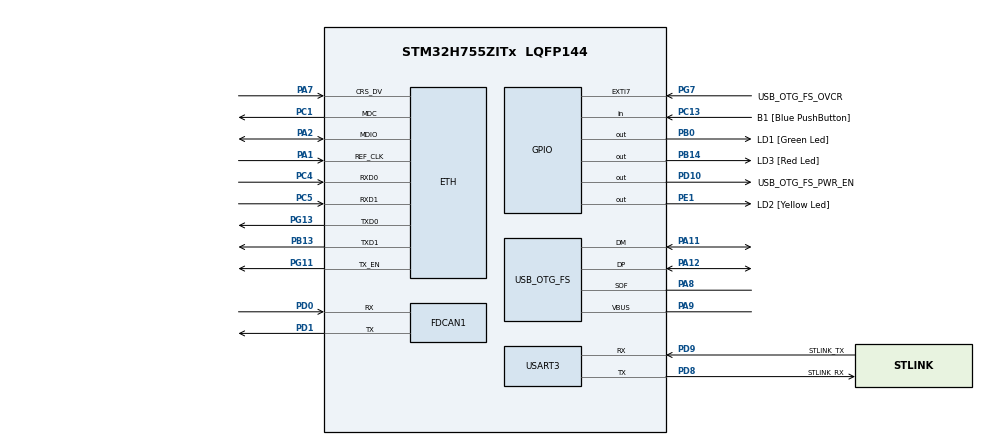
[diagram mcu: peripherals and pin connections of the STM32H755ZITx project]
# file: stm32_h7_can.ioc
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CortexM4.IPs=FATFS_M4\:I,FREERTOS_M4\:I,IWDG2\:I,RCC,WWDG2\:I,DMA,BDMA,MDMA,NVIC2\:I,ETH,USART3,DEBUG,USB_DEVICE_M4\:I,USB_HOST_M4\:I,PDM2PCM_M4\:I,PWR,RESMGR_UTILITY,SYS_M4\:I,CORTEX_M4\:I,OPENAMP_M4\:I,VREFBUF,GPIO
CortexM7.IPs=FATFS_M7\:I,FREERTOS_M7\:I,IWDG1\:I,RCC\:I,WWDG1\:I,DMA\:I,BDMA\:I,MDMA\:I,NVIC1\:I,ETH\:I,USART3\:I,USB_OTG_FS\:I,SYS\:I,CORTEX_M7\:I,DEBUG\:I,USB_DEVICE_M7\:I,USB_HOST_M7\:I,PDM2PCM_M7\:I,PWR\:I,RESMGR_UTILITY\:I,OPENAMP_M7\:I,VREFBUF\:I,GPIO\:I,FDCAN1\:I
ETH.MediaInterface=HAL_ETH_RMII_MODE
FDCAN1.CalculateBaudRateNominal=1499999
FDCAN1.CalculateTimeBitNominal=666
FDCAN1.CalculateTimeQuantumNominal=8.333333333333334
FDCAN1.NominalPrescaler=2
FDCAN1.NominalSyncJumpWidth=8
FDCAN1.NominalTimeSeg1=0x3F
FDCAN1.NominalTimeSeg2=16
FDCAN1.ProtocolException=ENABLE
FDCAN1.RxFifo0ElmtsNbr=1
FDCAN1.StdFiltersNbr=1
FDCAN1.TxFifoQueueElmtsNbr=1
Mcu.Family=STM32H7
Mcu.Name=STM32H755ZITx
Mcu.Package=LQFP144
NVIC1.PriorityGroup=NVIC_PRIORITYGROUP_4
NVIC2.PriorityGroup=NVIC_PRIORITYGROUP_4
PA1.Mode=RMII
PA1.PinAttribute=CortexM7
PA1.Signal=ETH_REF_CLK
PA11.Mode=Device_Only
PA11.PinAttribute=CortexM7
PA11.Signal=USB_OTG_FS_DM
PA12.Mode=Device_Only
PA12.PinAttribute=CortexM7
PA12.Signal=USB_OTG_FS_DP
PA2.Mode=RMII
PA2.PinAttribute=CortexM7
PA2.Signal=ETH_MDIO
PA7.Mode=RMII
PA7.PinAttribute=CortexM7
PA7.Signal=ETH_CRS_DV
PA8.Mode=Activate_SOF_FS
PA8.PinAttribute=CortexM7
PA8.Signal=USB_OTG_FS_SOF
PA9.Mode=Activate_VBUS
PA9.PinAttribute=CortexM7
PA9.Signal=USB_OTG_FS_VBUS
PB0.GPIO_Label=LD1 [Green Led]
PB0.PinAttribute=Free
PB0.Signal=GPIO_Output
PB13.Mode=RMII
PB13.PinAttribute=CortexM7
PB13.Signal=ETH_TXD1
PB14.GPIO_Label=LD3 [Red Led]
PB14.PinAttribute=Free
PB14.Signal=GPIO_Output
PC1.Mode=RMII
PC1.PinAttribute=CortexM7
PC1.Signal=ETH_MDC
PC13.GPIO_Label=B1 [Blue PushButton]
PC13.PinAttribute=Free
PC13.Signal=GPIO_Input
PC14-OSC32_IN\ (OSC32_IN).Mode=LSE-External-Oscillator
PC14-OSC32_IN\ (OSC32_IN).PinAttribute=CortexM7
PC14-OSC32_IN\ (OSC32_IN).Signal=RCC_OSC32_IN
PC15-OSC32_OUT\ (OSC32_OUT).Mode=LSE-External-Oscillator
PC15-OSC32_OUT\ (OSC32_OUT).PinAttribute=CortexM7
PC15-OSC32_OUT\ (OSC32_OUT).Signal=RCC_OSC32_OUT
PC4.Mode=RMII
PC4.PinAttribute=CortexM7
PC4.Signal=ETH_RXD0
PC5.Mode=RMII
PC5.PinAttribute=CortexM7
PC5.Signal=ETH_RXD1
PD0.Mode=FDCAN_Activate
PD0.PinAttribute=CortexM7
PD0.Signal=FDCAN1_RX
PD1.Mode=FDCAN_Activate
PD1.PinAttribute=CortexM7
PD1.Signal=FDCAN1_TX
PD10.GPIO_Label=USB_OTG_FS_PWR_EN
PD10.PinAttribute=Free
PD10.Signal=GPIO_Output
PD8.GPIO_Label=STLINK_RX
PD8.Mode=Asynchronous
PD8.PinAttribute=CortexM7
PD8.Signal=USART3_TX
PD9.GPIO_Label=STLINK_TX
PD9.Mode=Asynchronous
PD9.PinAttribute=CortexM7
PD9.Signal=USART3_RX
PE1.GPIO_Label=LD2 [Yellow Led]
PE1.PinAttribute=Free
PE1.Signal=GPIO_Output
PG11.Mode=RMII
PG11.PinAttribute=CortexM7
PG11.Signal=ETH_TX_EN
PG13.Mode=RMII
PG13.PinAttribute=CortexM7
PG13.Signal=ETH_TXD0
PG7.GPIO_Label=USB_OTG_FS_OVCR
PG7.PinAttribute=Free
PG7.Signal=GPXTI7
PH0-OSC_IN\ (PH0).Mode=HSE-External-Clock-Source
PH0-OSC_IN\ (PH0).PinAttribute=CortexM7
PH0-OSC_IN\ (PH0).Signal=RCC_OSC_IN
PH1-OSC_OUT\ (PH1).PinAttribute=CortexM7
PH1-OSC_OUT\ (PH1).Signal=RCC_OSC_OUT
ProjectManager.HeapSize=M4-0x200,M7-0x200
ProjectManager.StackSize=M4-0x400,M7-0x400
ProjectManager.TargetToolchain=STM32CubeIDE
RCC.ADCFreq_Value=129000000
RCC.APB1Freq_Value=30000000
RCC.APB2Freq_Value=60000000
RCC.APB3Freq_Value=60000000
RCC.APB4Freq_Value=60000000
RCC.CortexFreq_Value=120000000
RCC.D1CPRE=RCC_SYSCLK_DIV2
RCC.D2PPRE1=RCC_APB1_DIV2
RCC.DIVM1=4
RCC.DIVN1=60
RCC.DIVP1=4
RCC.DIVQ1=4
RCC.HCLKFreq_Value=60000000
RCC.HPRE=RCC_HCLK_DIV2
RCC.HSE_VALUE=8000000
RCC.PLL2FRACN=0
RCC.PLL3FRACN=0
RCC.PLLFRACN=0
RCC.PLLSourceVirtualString=RCC_PLLSOURCE_HSI
RCC.PWR_Regulator_Voltage_Scale=PWR_REGULATOR_VOLTAGE_SCALE2
RCC.SYSCLKFreq_VALUE=240000000
RCC.SYSCLKSource=RCC_SYSCLKSOURCE_PLLCLK
RCC.SupplySource=PWR_DIRECT_SMPS_SUPPLY
RCC.USBFreq_Value=240000000
USART3.VirtualMode-Asynchronous=VM_ASYNC
USB_OTG_FS.VirtualMode=Device_Only
VP_SYS_M4_VS_Systick.Mode=SysTick
board=NUCLEO-H755ZI-Q

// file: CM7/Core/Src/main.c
/* USER CODE BEGIN Header */
/**
  ******************************************************************************
  * @file           : main.c
  * @brief          : Main program body
  ******************************************************************************
  * @attention
  *
  * Copyright (c) 2024 STMicroelectronics.
  * All rights reserved.
  *
  * This software is licensed under terms that can be found in the LICENSE file
  * in the root directory of this software component.
  * If no LICENSE file comes with this software, it is provided AS-IS.
  *
  ******************************************************************************
  */
/* USER CODE END Header */
#include "main.h"
#include "string.h"

/* USER CODE BEGIN PD */

#ifndef HSEM_ID_0
#define HSEM_ID_0 (0U) /* HW semaphore 0*/
#endif
/* USER CODE END PD */

#if defined ( __ICCARM__ ) /*!< IAR Compiler */
#pragma location=0x30000000
ETH_DMADescTypeDef  DMARxDscrTab[ETH_RX_DESC_CNT]; /* Ethernet Rx DMA Descriptors */
#pragma location=0x30000200
ETH_DMADescTypeDef  DMATxDscrTab[ETH_TX_DESC_CNT]; /* Ethernet Tx DMA Descriptors */

#elif defined ( __CC_ARM )  /* MDK ARM Compiler */

__attribute__((at(0x30000000))) ETH_DMADescTypeDef  DMARxDscrTab[ETH_RX_DESC_CNT]; /* Ethernet Rx DMA Descriptors */
__attribute__((at(0x30000200))) ETH_DMADescTypeDef  DMATxDscrTab[ETH_TX_DESC_CNT]; /* Ethernet Tx DMA Descriptors */

#elif defined ( __GNUC__ ) /* GNU Compiler */
ETH_DMADescTypeDef DMARxDscrTab[ETH_RX_DESC_CNT] __attribute__((section(".RxDecripSection"))); /* Ethernet Rx DMA Descriptors */
ETH_DMADescTypeDef DMATxDscrTab[ETH_TX_DESC_CNT] __attribute__((section(".TxDecripSection")));   /* Ethernet Tx DMA Descriptors */

#endif

ETH_TxPacketConfig TxConfig;

ETH_HandleTypeDef heth;

FDCAN_HandleTypeDef hfdcan1;

UART_HandleTypeDef huart3;

PCD_HandleTypeDef hpcd_USB_OTG_FS;

/* USER CODE BEGIN PV */
FDCAN_FilterTypeDef sFilterConfig;
FDCAN_TxHeaderTypeDef TxHeader;
FDCAN_RxHeaderTypeDef RxHeader;
uint8_t TxData[8] = {0x10, 0x34, 0x54, 0x76, 0x98, 0x00, 0x11, 0x22};
uint8_t RxData[8];
/* USER CODE END PV */

void SystemClock_Config(void);
static void MX_GPIO_Init(void);
static void MX_ETH_Init(void);
static void MX_USART3_UART_Init(void);
static void MX_USB_OTG_FS_PCD_Init(void);
static void MX_FDCAN1_Init(void);

int main(void)
{
/* USER CODE BEGIN Boot_Mode_Sequence_0 */
  int32_t timeout;
/* USER CODE END Boot_Mode_Sequence_0 */

/* USER CODE BEGIN Boot_Mode_Sequence_1 */
  /* Wait until CPU2 boots and enters in stop mode or timeout*/
  timeout = 0xFFFF;
  while((__HAL_RCC_GET_FLAG(RCC_FLAG_D2CKRDY) != RESET) && (timeout-- > 0));
  if ( timeout < 0 )
  {
  Error_Handler();
  }
/* USER CODE END Boot_Mode_Sequence_1 */
  /* MCU Configuration--------------------------------------------------------*/

  /* Reset of all peripherals, Initializes the Flash interface and the Systick. */
  HAL_Init();

  /* Configure the system clock */
  SystemClock_Config();
/* USER CODE BEGIN Boot_Mode_Sequence_2 */
/* When system initialization is finished, Cortex-M7 will release Cortex-M4 by means of
HSEM notification */
/*HW semaphore Clock enable*/
__HAL_RCC_HSEM_CLK_ENABLE();
/*Take HSEM */
HAL_HSEM_FastTake(HSEM_ID_0);
/*Release HSEM in order to notify the CPU2(CM4)*/
HAL_HSEM_Release(HSEM_ID_0,0);
/* wait until CPU2 wakes up from stop mode */
timeout = 0xFFFF;
while((__HAL_RCC_GET_FLAG(RCC_FLAG_D2CKRDY) == RESET) && (timeout-- > 0));
if ( timeout < 0 )
{
Error_Handler();
}
/* USER CODE END Boot_Mode_Sequence_2 */

  /* Initialize all configured peripherals */
  MX_GPIO_Init();
  MX_ETH_Init();
  MX_USART3_UART_Init();
  MX_USB_OTG_FS_PCD_Init();
  MX_FDCAN1_Init();

  /* Infinite loop */
  /* USER CODE BEGIN WHILE */
  printf("Welcome to the CANbus!!!\n\r");
//  while (1){
//  	while (HAL_FDCAN_GetRxMessage(&hfdcan1, FDCAN_RX_FIFO0, &RxHeader, RxData) != HAL_OK);
//  	HAL_Delay(10);
//  	printf("\n\rCAN ID: %lx", RxHeader.Identifier);
//  	//HAL_GPIO_TogglePin(LD1_GPIO_Port,LD1_Pin);
//  	HAL_Delay(100); /*AAO-*/
//  }

  while (1) {
      // Wait until a CAN message is received
      while (HAL_FDCAN_GetRxMessage(&hfdcan1, FDCAN_RX_FIFO0, &RxHeader, RxData) != HAL_OK);

      // Delay for 10 ms
      HAL_Delay(10);

      // Print CAN ID
      printf("\n\r0x%lx", RxHeader.Identifier);

      // Print the CAN data length and data bytes
      printf(" [%lu]", RxHeader.DataLength >> 16);  // Data length is stored in bits 16-19
      printf(" ");

      // Loop through each byte of the CAN message data and print it
      for (int i = 0; i < (RxHeader.DataLength >> 16); i++) {
          printf("0x%02X ", RxData[i]);  // Print each byte in hexadecimal
      }

      // Optional: toggle LED for visual feedback (commented out)
      // HAL_GPIO_TogglePin(LD1_GPIO_Port, LD1_Pin);

      // Delay for 100 ms
      HAL_Delay(100);
  }

    /* USER CODE END WHILE */

}

void SystemClock_Config(void)
{
  RCC_OscInitTypeDef RCC_OscInitStruct = {0};
  RCC_ClkInitTypeDef RCC_ClkInitStruct = {0};

  /** Supply configuration update enable
  */
  HAL_PWREx_ConfigSupply(PWR_DIRECT_SMPS_SUPPLY);

  /** Configure the main internal regulator output voltage
  */
  __HAL_PWR_VOLTAGESCALING_CONFIG(PWR_REGULATOR_VOLTAGE_SCALE2);

  while(!__HAL_PWR_GET_FLAG(PWR_FLAG_VOSRDY)) {}

  /** Initializes the RCC Oscillators according to the specified parameters
  * in the RCC_OscInitTypeDef structure.
  */
  RCC_OscInitStruct.OscillatorType = RCC_OSCILLATORTYPE_HSE;
  RCC_OscInitStruct.HSEState = RCC_HSE_BYPASS;
  RCC_OscInitStruct.PLL.PLLState = RCC_PLL_ON;
  RCC_OscInitStruct.PLL.PLLSource = RCC_PLLSOURCE_HSE;
  RCC_OscInitStruct.PLL.PLLM = 1;
  RCC_OscInitStruct.PLL.PLLN = 20;
  RCC_OscInitStruct.PLL.PLLP = 2;
  RCC_OscInitStruct.PLL.PLLQ = 4;
  RCC_OscInitStruct.PLL.PLLR = 2;
  RCC_OscInitStruct.PLL.PLLRGE = RCC_PLL1VCIRANGE_3;
  RCC_OscInitStruct.PLL.PLLVCOSEL = RCC_PLL1VCOMEDIUM;
  RCC_OscInitStruct.PLL.PLLFRACN = 0;
  if (HAL_RCC_OscConfig(&RCC_OscInitStruct) != HAL_OK)
  {
    Error_Handler();
  }

  /** Initializes the CPU, AHB and APB buses clocks
  */
  RCC_ClkInitStruct.ClockType = RCC_CLOCKTYPE_HCLK|RCC_CLOCKTYPE_SYSCLK
                              |RCC_CLOCKTYPE_PCLK1|RCC_CLOCKTYPE_PCLK2
                              |RCC_CLOCKTYPE_D3PCLK1|RCC_CLOCKTYPE_D1PCLK1;
  RCC_ClkInitStruct.SYSCLKSource = RCC_SYSCLKSOURCE_PLLCLK;
  RCC_ClkInitStruct.SYSCLKDivider = RCC_SYSCLK_DIV1;
  RCC_ClkInitStruct.AHBCLKDivider = RCC_HCLK_DIV1;
  RCC_ClkInitStruct.APB3CLKDivider = RCC_APB3_DIV1;
  RCC_ClkInitStruct.APB1CLKDivider = RCC_APB1_DIV2;
  RCC_ClkInitStruct.APB2CLKDivider = RCC_APB2_DIV1;
  RCC_ClkInitStruct.APB4CLKDivider = RCC_APB4_DIV1;

  if (HAL_RCC_ClockConfig(&RCC_ClkInitStruct, FLASH_LATENCY_1) != HAL_OK)
  {
    Error_Handler();
  }
}

static void MX_ETH_Init(void)
{

   static uint8_t MACAddr[6];

  heth.Instance = ETH;
  MACAddr[0] = 0x00;
  MACAddr[1] = 0x80;
  MACAddr[2] = 0xE1;
  MACAddr[3] = 0x00;
  MACAddr[4] = 0x00;
  MACAddr[5] = 0x00;
  heth.Init.MACAddr = &MACAddr[0];
  heth.Init.MediaInterface = HAL_ETH_RMII_MODE;
  heth.Init.TxDesc = DMATxDscrTab;
  heth.Init.RxDesc = DMARxDscrTab;
  heth.Init.RxBuffLen = 1524;

  if (HAL_ETH_Init(&heth) != HAL_OK)
  {
    Error_Handler();
  }

  memset(&TxConfig, 0 , sizeof(ETH_TxPacketConfig));
  TxConfig.Attributes = ETH_TX_PACKETS_FEATURES_CSUM | ETH_TX_PACKETS_FEATURES_CRCPAD;
  TxConfig.ChecksumCtrl = ETH_CHECKSUM_IPHDR_PAYLOAD_INSERT_PHDR_CALC;
  TxConfig.CRCPadCtrl = ETH_CRC_PAD_INSERT;

}

static void MX_FDCAN1_Init(void)
{

  hfdcan1.Instance = FDCAN1;
  hfdcan1.Init.FrameFormat = FDCAN_FRAME_CLASSIC;
  hfdcan1.Init.Mode = FDCAN_MODE_NORMAL;
  hfdcan1.Init.AutoRetransmission = DISABLE;
  hfdcan1.Init.TransmitPause = DISABLE;
  hfdcan1.Init.ProtocolException = ENABLE;
  hfdcan1.Init.NominalPrescaler = 2;
  hfdcan1.Init.NominalSyncJumpWidth = 8;
  hfdcan1.Init.NominalTimeSeg1 = 0x3F;
  hfdcan1.Init.NominalTimeSeg2 = 16;
  hfdcan1.Init.DataPrescaler = 1;
  hfdcan1.Init.DataSyncJumpWidth = 1;
  hfdcan1.Init.DataTimeSeg1 = 1;
  hfdcan1.Init.DataTimeSeg2 = 1;
  hfdcan1.Init.MessageRAMOffset = 0;
  hfdcan1.Init.StdFiltersNbr = 1;
  hfdcan1.Init.ExtFiltersNbr = 0;
  hfdcan1.Init.RxFifo0ElmtsNbr = 1;
  hfdcan1.Init.RxFifo0ElmtSize = FDCAN_DATA_BYTES_8;
  hfdcan1.Init.RxFifo1ElmtsNbr = 0;
  hfdcan1.Init.RxFifo1ElmtSize = FDCAN_DATA_BYTES_8;
  hfdcan1.Init.RxBuffersNbr = 0;
  hfdcan1.Init.RxBufferSize = FDCAN_DATA_BYTES_8;
  hfdcan1.Init.TxEventsNbr = 0;
  hfdcan1.Init.TxBuffersNbr = 0;
  hfdcan1.Init.TxFifoQueueElmtsNbr = 1;
  hfdcan1.Init.TxFifoQueueMode = FDCAN_TX_FIFO_OPERATION;
  hfdcan1.Init.TxElmtSize = FDCAN_DATA_BYTES_8;
  if (HAL_FDCAN_Init(&hfdcan1) != HAL_OK)
  {
    Error_Handler();
  }
  /* USER CODE BEGIN FDCAN1_Init 2 */
  /*AAO+*/
   /* Configure Rx filter */
    sFilterConfig.IdType = FDCAN_STANDARD_ID;
    sFilterConfig.FilterIndex = 0;
    sFilterConfig.FilterType = FDCAN_FILTER_MASK;
    sFilterConfig.FilterConfig = FDCAN_FILTER_TO_RXFIFO0;
    // Default
//    sFilterConfig.FilterID1 = 0x000; // Filter
//    sFilterConfig.FilterID2 = 0x000; // Mask
    // InClass CAN
    sFilterConfig.FilterID1 = 0x300; // Filter
    sFilterConfig.FilterID2 = 0x700; // Mask

//    sFilterConfig.FilterID1 = 0x617; // Filter
//    sFilterConfig.FilterID2 = 0x7FF; // Mask

    /* Configure global filter to reject all non-matching frames */
    HAL_FDCAN_ConfigGlobalFilter(&hfdcan1, FDCAN_REJECT, FDCAN_REJECT, FDCAN_REJECT_REMOTE, FDCAN_REJECT_REMOTE);

    if (HAL_FDCAN_ConfigFilter(&hfdcan1, &sFilterConfig) != HAL_OK)
      {
         /* Filter configuration Error */
         Error_Handler();
      }
     /* Start the FDCAN module */
    if (HAL_FDCAN_Start(&hfdcan1) != HAL_OK) {
      }
         /* Start Error */
    if (HAL_FDCAN_ActivateNotification(&hfdcan1, FDCAN_IT_RX_FIFO0_NEW_MESSAGE, 0) != HAL_OK) {
      }
         /* Notification Error */

     /* Configure Tx buffer message */
    TxHeader.Identifier = 0x111;
    TxHeader.IdType = FDCAN_STANDARD_ID;
    TxHeader.TxFrameType = FDCAN_DATA_FRAME;
    TxHeader.DataLength = FDCAN_DLC_BYTES_12;
    TxHeader.ErrorStateIndicator = FDCAN_ESI_ACTIVE;
    TxHeader.BitRateSwitch = FDCAN_BRS_ON;
    TxHeader.FDFormat = FDCAN_FD_CAN;
    TxHeader.TxEventFifoControl = FDCAN_NO_TX_EVENTS;
    TxHeader.MessageMarker = 0x00;
   /*AAO-*/
  /* USER CODE END FDCAN1_Init 2 */

}

static void MX_USART3_UART_Init(void)
{

  huart3.Instance = USART3;
  huart3.Init.BaudRate = 115200;
  huart3.Init.WordLength = UART_WORDLENGTH_8B;
  huart3.Init.StopBits = UART_STOPBITS_1;
  huart3.Init.Parity = UART_PARITY_NONE;
  huart3.Init.Mode = UART_MODE_TX_RX;
  huart3.Init.HwFlowCtl = UART_HWCONTROL_NONE;
  huart3.Init.OverSampling = UART_OVERSAMPLING_16;
  huart3.Init.OneBitSampling = UART_ONE_BIT_SAMPLE_DISABLE;
  huart3.Init.ClockPrescaler = UART_PRESCALER_DIV1;
  huart3.AdvancedInit.AdvFeatureInit = UART_ADVFEATURE_NO_INIT;
  if (HAL_UART_Init(&huart3) != HAL_OK)
  {
    Error_Handler();
  }
  if (HAL_UARTEx_SetTxFifoThreshold(&huart3, UART_TXFIFO_THRESHOLD_1_8) != HAL_OK)
  {
    Error_Handler();
  }
  if (HAL_UARTEx_SetRxFifoThreshold(&huart3, UART_RXFIFO_THRESHOLD_1_8) != HAL_OK)
  {
    Error_Handler();
  }
  if (HAL_UARTEx_DisableFifoMode(&huart3) != HAL_OK)
  {
    Error_Handler();
  }

}

static void MX_USB_OTG_FS_PCD_Init(void)
{

  hpcd_USB_OTG_FS.Instance = USB_OTG_FS;
  hpcd_USB_OTG_FS.Init.dev_endpoints = 9;
  hpcd_USB_OTG_FS.Init.speed = PCD_SPEED_FULL;
  hpcd_USB_OTG_FS.Init.dma_enable = DISABLE;
  hpcd_USB_OTG_FS.Init.phy_itface = PCD_PHY_EMBEDDED;
  hpcd_USB_OTG_FS.Init.Sof_enable = DISABLE;
  hpcd_USB_OTG_FS.Init.low_power_enable = DISABLE;
  hpcd_USB_OTG_FS.Init.lpm_enable = DISABLE;
  hpcd_USB_OTG_FS.Init.battery_charging_enable = ENABLE;
  hpcd_USB_OTG_FS.Init.vbus_sensing_enable = ENABLE;
  hpcd_USB_OTG_FS.Init.use_dedicated_ep1 = DISABLE;
  if (HAL_PCD_Init(&hpcd_USB_OTG_FS) != HAL_OK)
  {
    Error_Handler();
  }

}

static void MX_GPIO_Init(void)
{

  /* GPIO Ports Clock Enable */
  __HAL_RCC_GPIOC_CLK_ENABLE();
  __HAL_RCC_GPIOH_CLK_ENABLE();
  __HAL_RCC_GPIOA_CLK_ENABLE();
  __HAL_RCC_GPIOB_CLK_ENABLE();
  __HAL_RCC_GPIOD_CLK_ENABLE();
  __HAL_RCC_GPIOG_CLK_ENABLE();

}

void Error_Handler(void)
{
  __disable_irq();
  while (1)
  {
  }
}
